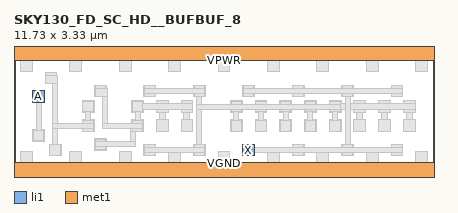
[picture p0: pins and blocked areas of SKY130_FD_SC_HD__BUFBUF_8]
MACRO SKY130_FD_SC_HD__BUFBUF_8
 CLASS CORE ;
 FOREIGN SKY130_FD_SC_HD__BUFBUF_8 0 0 ;
 SIZE 11.73 BY 3.33 ;
 ORIGIN 0 0 ;
 SYMMETRY X Y R90 ;
 SITE unit ;
  PIN VPWR
   DIRECTION INOUT ;
   USE POWER ;
   SHAPE ABUTMENT ;
    PORT
     CLASS CORE ;
       LAYER li1 ;
        RECT 0.00000000 3.09000000 11.73000000 3.57000000 ;
       LAYER met1 ;
        RECT 0.00000000 3.09000000 11.73000000 3.57000000 ;
    END
  END VPWR

  PIN VGND
   DIRECTION INOUT ;
   USE POWER ;
   SHAPE ABUTMENT ;
    PORT
     CLASS CORE ;
       LAYER li1 ;
        RECT 0.00000000 -0.24000000 11.73000000 0.24000000 ;
       LAYER met1 ;
        RECT 0.00000000 -0.24000000 11.73000000 0.24000000 ;
    END
  END VGND

  PIN X
   DIRECTION INOUT ;
   USE SIGNAL ;
   SHAPE ABUTMENT ;
    PORT
     CLASS CORE ;
       LAYER li1 ;
        RECT 6.39000000 0.42000000 6.72000000 0.75000000 ;
    END
  END X

  PIN A
   DIRECTION INOUT ;
   USE SIGNAL ;
   SHAPE ABUTMENT ;
    PORT
     CLASS CORE ;
       LAYER li1 ;
        RECT 0.52500000 1.90500000 0.85500000 2.23500000 ;
    END
  END A

 OBS
    LAYER polycont ;
     RECT 0.60500000 0.90500000 0.77500000 1.07500000 ;
     RECT 1.98500000 1.17500000 2.15500000 1.34500000 ;
     RECT 3.36500000 1.17500000 3.53500000 1.34500000 ;
     RECT 4.05500000 1.17500000 4.22500000 1.34500000 ;
     RECT 4.74500000 1.17500000 4.91500000 1.34500000 ;
     RECT 6.12500000 1.17500000 6.29500000 1.34500000 ;
     RECT 6.81500000 1.17500000 6.98500000 1.34500000 ;
     RECT 7.50500000 1.17500000 7.67500000 1.34500000 ;
     RECT 8.19500000 1.17500000 8.36500000 1.34500000 ;
     RECT 8.88500000 1.17500000 9.05500000 1.34500000 ;
     RECT 9.57500000 1.17500000 9.74500000 1.34500000 ;
     RECT 10.26500000 1.17500000 10.43500000 1.34500000 ;
     RECT 10.95500000 1.17500000 11.12500000 1.34500000 ;
     RECT 1.98500000 1.71500000 2.15500000 1.88500000 ;
     RECT 3.36500000 1.71500000 3.53500000 1.88500000 ;
     RECT 4.05500000 1.71500000 4.22500000 1.88500000 ;
     RECT 4.74500000 1.71500000 4.91500000 1.88500000 ;
     RECT 6.12500000 1.71500000 6.29500000 1.88500000 ;
     RECT 6.81500000 1.71500000 6.98500000 1.88500000 ;
     RECT 7.50500000 1.71500000 7.67500000 1.88500000 ;
     RECT 8.19500000 1.71500000 8.36500000 1.88500000 ;
     RECT 8.88500000 1.71500000 9.05500000 1.88500000 ;
     RECT 9.57500000 1.71500000 9.74500000 1.88500000 ;
     RECT 10.26500000 1.71500000 10.43500000 1.88500000 ;
     RECT 10.95500000 1.71500000 11.12500000 1.88500000 ;
     RECT 0.60500000 1.98500000 0.77500000 2.15500000 ;

    LAYER pdiffc ;
     RECT 2.33000000 2.15000000 2.50000000 2.32000000 ;
     RECT 3.71000000 2.15000000 3.88000000 2.32000000 ;
     RECT 5.09000000 2.15000000 5.26000000 2.32000000 ;
     RECT 6.47000000 2.15000000 6.64000000 2.32000000 ;
     RECT 7.85000000 2.15000000 8.02000000 2.32000000 ;
     RECT 9.23000000 2.15000000 9.40000000 2.32000000 ;
     RECT 10.61000000 2.15000000 10.78000000 2.32000000 ;
     RECT 0.95000000 2.51000000 1.12000000 2.68000000 ;
     RECT 0.26000000 2.86000000 0.43000000 3.03000000 ;
     RECT 1.64000000 2.86000000 1.81000000 3.03000000 ;
     RECT 3.02000000 2.86000000 3.19000000 3.03000000 ;
     RECT 4.40000000 2.86000000 4.57000000 3.03000000 ;
     RECT 5.78000000 2.86000000 5.95000000 3.03000000 ;
     RECT 7.16000000 2.86000000 7.33000000 3.03000000 ;
     RECT 8.54000000 2.86000000 8.71000000 3.03000000 ;
     RECT 9.92000000 2.86000000 10.09000000 3.03000000 ;
     RECT 11.30000000 2.86000000 11.47000000 3.03000000 ;

    LAYER ndiffc ;
     RECT 0.26000000 0.30000000 0.43000000 0.47000000 ;
     RECT 1.64000000 0.30000000 1.81000000 0.47000000 ;
     RECT 3.02000000 0.30000000 3.19000000 0.47000000 ;
     RECT 4.40000000 0.30000000 4.57000000 0.47000000 ;
     RECT 5.78000000 0.30000000 5.95000000 0.47000000 ;
     RECT 7.16000000 0.30000000 7.33000000 0.47000000 ;
     RECT 8.54000000 0.30000000 8.71000000 0.47000000 ;
     RECT 9.92000000 0.30000000 10.09000000 0.47000000 ;
     RECT 11.30000000 0.30000000 11.47000000 0.47000000 ;
     RECT 1.06500000 0.50000000 1.23500000 0.67000000 ;
     RECT 3.71000000 0.50000000 3.88000000 0.67000000 ;
     RECT 5.09000000 0.50000000 5.26000000 0.67000000 ;
     RECT 6.47000000 0.50000000 6.64000000 0.67000000 ;
     RECT 7.85000000 0.50000000 8.02000000 0.67000000 ;
     RECT 9.23000000 0.50000000 9.40000000 0.67000000 ;
     RECT 10.61000000 0.50000000 10.78000000 0.67000000 ;
     RECT 2.33000000 0.66000000 2.50000000 0.83000000 ;

    LAYER li1 ;
     RECT 0.00000000 -0.24000000 11.73000000 0.24000000 ;
     RECT 0.18000000 0.24000000 0.51000000 0.55000000 ;
     RECT 1.56000000 0.24000000 1.89000000 0.55000000 ;
     RECT 2.94000000 0.24000000 3.27000000 0.55000000 ;
     RECT 4.32000000 0.24000000 4.65000000 0.55000000 ;
     RECT 5.70000000 0.24000000 6.03000000 0.55000000 ;
     RECT 7.08000000 0.24000000 7.41000000 0.55000000 ;
     RECT 8.46000000 0.24000000 8.79000000 0.55000000 ;
     RECT 9.84000000 0.24000000 10.17000000 0.55000000 ;
     RECT 11.22000000 0.24000000 11.55000000 0.55000000 ;
     RECT 0.98500000 0.42000000 1.31500000 0.75000000 ;
     RECT 3.63000000 0.42000000 3.96000000 0.75000000 ;
     RECT 5.01000000 0.42000000 5.34000000 0.75000000 ;
     RECT 6.39000000 0.42000000 6.72000000 0.75000000 ;
     RECT 7.77000000 0.42000000 8.10000000 0.75000000 ;
     RECT 9.15000000 0.42000000 9.48000000 0.75000000 ;
     RECT 10.53000000 0.42000000 10.86000000 0.75000000 ;
     RECT 2.25000000 0.58000000 2.58000000 0.91000000 ;
     RECT 0.52500000 0.82500000 0.85500000 1.15500000 ;
     RECT 1.90500000 1.09500000 2.23500000 1.42500000 ;
     RECT 3.28500000 1.09500000 3.61500000 1.42500000 ;
     RECT 6.04500000 1.09500000 6.37500000 1.42500000 ;
     RECT 6.73500000 1.09500000 7.06500000 1.42500000 ;
     RECT 7.42500000 1.09500000 7.75500000 1.42500000 ;
     RECT 8.11500000 1.09500000 8.44500000 1.42500000 ;
     RECT 8.80500000 1.09500000 9.13500000 1.42500000 ;
     RECT 1.90500000 1.63500000 2.23500000 1.96500000 ;
     RECT 3.97500000 1.09500000 4.30500000 1.42500000 ;
     RECT 4.66500000 1.09500000 4.99500000 1.42500000 ;
     RECT 4.05500000 1.42500000 4.22500000 1.63500000 ;
     RECT 4.74500000 1.42500000 4.91500000 1.63500000 ;
     RECT 3.28500000 1.63500000 3.61500000 1.71500000 ;
     RECT 3.97500000 1.63500000 4.30500000 1.71500000 ;
     RECT 4.66500000 1.63500000 4.99500000 1.71500000 ;
     RECT 3.28500000 1.71500000 4.99500000 1.88500000 ;
     RECT 3.28500000 1.88500000 3.61500000 1.96500000 ;
     RECT 3.97500000 1.88500000 4.30500000 1.96500000 ;
     RECT 4.66500000 1.88500000 4.99500000 1.96500000 ;
     RECT 6.04500000 1.63500000 6.37500000 1.96500000 ;
     RECT 6.73500000 1.63500000 7.06500000 1.96500000 ;
     RECT 7.42500000 1.63500000 7.75500000 1.96500000 ;
     RECT 8.11500000 1.63500000 8.44500000 1.96500000 ;
     RECT 9.49500000 1.09500000 9.82500000 1.42500000 ;
     RECT 10.18500000 1.09500000 10.51500000 1.42500000 ;
     RECT 10.87500000 1.09500000 11.20500000 1.42500000 ;
     RECT 9.57500000 1.42500000 9.74500000 1.63500000 ;
     RECT 10.26500000 1.42500000 10.43500000 1.63500000 ;
     RECT 10.95500000 1.42500000 11.12500000 1.63500000 ;
     RECT 8.80500000 1.63500000 9.13500000 1.71500000 ;
     RECT 9.49500000 1.63500000 9.82500000 1.71500000 ;
     RECT 10.18500000 1.63500000 10.51500000 1.71500000 ;
     RECT 10.87500000 1.63500000 11.20500000 1.71500000 ;
     RECT 8.80500000 1.71500000 11.20500000 1.88500000 ;
     RECT 8.80500000 1.88500000 9.13500000 1.96500000 ;
     RECT 9.49500000 1.88500000 9.82500000 1.96500000 ;
     RECT 10.18500000 1.88500000 10.51500000 1.96500000 ;
     RECT 10.87500000 1.88500000 11.20500000 1.96500000 ;
     RECT 0.52500000 1.90500000 0.85500000 2.23500000 ;
     RECT 2.25000000 2.07000000 2.58000000 2.40000000 ;
     RECT 3.63000000 2.07000000 3.96000000 2.40000000 ;
     RECT 5.01000000 2.07000000 5.34000000 2.40000000 ;
     RECT 6.39000000 2.07000000 6.72000000 2.40000000 ;
     RECT 7.77000000 2.07000000 8.10000000 2.40000000 ;
     RECT 9.15000000 2.07000000 9.48000000 2.40000000 ;
     RECT 10.53000000 2.07000000 10.86000000 2.40000000 ;
     RECT 0.87000000 2.43000000 1.20000000 2.76000000 ;
     RECT 0.18000000 2.78000000 0.51000000 3.09000000 ;
     RECT 1.56000000 2.78000000 1.89000000 3.09000000 ;
     RECT 2.94000000 2.78000000 3.27000000 3.09000000 ;
     RECT 4.32000000 2.78000000 4.65000000 3.09000000 ;
     RECT 5.70000000 2.78000000 6.03000000 3.09000000 ;
     RECT 7.08000000 2.78000000 7.41000000 3.09000000 ;
     RECT 8.46000000 2.78000000 8.79000000 3.09000000 ;
     RECT 9.84000000 2.78000000 10.17000000 3.09000000 ;
     RECT 11.22000000 2.78000000 11.55000000 3.09000000 ;
     RECT 0.00000000 3.09000000 11.73000000 3.57000000 ;

    LAYER viali ;
     RECT 0.26000000 -0.08500000 0.43000000 0.08500000 ;
     RECT 1.06500000 0.50000000 1.23500000 0.67000000 ;
     RECT 3.71000000 0.50000000 3.88000000 0.67000000 ;
     RECT 5.09000000 0.50000000 5.26000000 0.67000000 ;
     RECT 6.47000000 0.50000000 6.64000000 0.67000000 ;
     RECT 7.85000000 0.50000000 8.02000000 0.67000000 ;
     RECT 9.23000000 0.50000000 9.40000000 0.67000000 ;
     RECT 10.61000000 0.50000000 10.78000000 0.67000000 ;
     RECT 2.33000000 0.66000000 2.50000000 0.83000000 ;
     RECT 0.60500000 0.90500000 0.77500000 1.07500000 ;
     RECT 1.98500000 1.17500000 2.15500000 1.34500000 ;
     RECT 3.36500000 1.17500000 3.53500000 1.34500000 ;
     RECT 6.12500000 1.17500000 6.29500000 1.34500000 ;
     RECT 6.81500000 1.17500000 6.98500000 1.34500000 ;
     RECT 7.50500000 1.17500000 7.67500000 1.34500000 ;
     RECT 8.19500000 1.17500000 8.36500000 1.34500000 ;
     RECT 8.88500000 1.17500000 9.05500000 1.34500000 ;
     RECT 1.98500000 1.71500000 2.15500000 1.88500000 ;
     RECT 3.36500000 1.71500000 3.53500000 1.88500000 ;
     RECT 6.12500000 1.71500000 6.29500000 1.88500000 ;
     RECT 6.81500000 1.71500000 6.98500000 1.88500000 ;
     RECT 7.50500000 1.71500000 7.67500000 1.88500000 ;
     RECT 8.19500000 1.71500000 8.36500000 1.88500000 ;
     RECT 8.88500000 1.71500000 9.05500000 1.88500000 ;
     RECT 0.60500000 1.98500000 0.77500000 2.15500000 ;
     RECT 2.33000000 2.15000000 2.50000000 2.32000000 ;
     RECT 3.71000000 2.15000000 3.88000000 2.32000000 ;
     RECT 5.09000000 2.15000000 5.26000000 2.32000000 ;
     RECT 6.47000000 2.15000000 6.64000000 2.32000000 ;
     RECT 7.85000000 2.15000000 8.02000000 2.32000000 ;
     RECT 9.23000000 2.15000000 9.40000000 2.32000000 ;
     RECT 10.61000000 2.15000000 10.78000000 2.32000000 ;
     RECT 0.95000000 2.51000000 1.12000000 2.68000000 ;
     RECT 4.40000000 3.24500000 4.57000000 3.41500000 ;

    LAYER met1 ;
     RECT 0.00000000 -0.24000000 11.73000000 0.24000000 ;
     RECT 0.54500000 0.84500000 0.83500000 1.13500000 ;
     RECT 0.62000000 1.13500000 0.76000000 1.92500000 ;
     RECT 0.54500000 1.92500000 0.83500000 2.21500000 ;
     RECT 2.27000000 0.60000000 2.56000000 0.67500000 ;
     RECT 2.27000000 0.67500000 3.40500000 0.81500000 ;
     RECT 2.27000000 0.81500000 2.56000000 0.89000000 ;
     RECT 3.26500000 0.81500000 3.40500000 1.11500000 ;
     RECT 3.26500000 1.11500000 3.59500000 1.19000000 ;
     RECT 2.46000000 1.19000000 3.59500000 1.33000000 ;
     RECT 3.30500000 1.33000000 3.59500000 1.40500000 ;
     RECT 3.38000000 1.40500000 3.52000000 1.65500000 ;
     RECT 3.30500000 1.65500000 3.59500000 1.94500000 ;
     RECT 2.46000000 1.33000000 2.60000000 2.09000000 ;
     RECT 2.27000000 2.09000000 2.60000000 2.30500000 ;
     RECT 2.27000000 2.30500000 2.56000000 2.38000000 ;
     RECT 3.65000000 0.44000000 3.94000000 0.51500000 ;
     RECT 5.03000000 0.44000000 5.32000000 0.51500000 ;
     RECT 3.65000000 0.51500000 5.32000000 0.65500000 ;
     RECT 3.65000000 0.65500000 3.94000000 0.73000000 ;
     RECT 5.03000000 0.65500000 5.32000000 0.73000000 ;
     RECT 6.06500000 1.11500000 6.35500000 1.40500000 ;
     RECT 6.75500000 1.11500000 7.04500000 1.40500000 ;
     RECT 7.44500000 1.11500000 7.73500000 1.40500000 ;
     RECT 8.13500000 1.11500000 8.42500000 1.40500000 ;
     RECT 8.82500000 1.11500000 9.11500000 1.40500000 ;
     RECT 6.14000000 1.40500000 6.28000000 1.65500000 ;
     RECT 6.83000000 1.40500000 6.97000000 1.65500000 ;
     RECT 7.52000000 1.40500000 7.66000000 1.65500000 ;
     RECT 8.21000000 1.40500000 8.35000000 1.65500000 ;
     RECT 8.90000000 1.40500000 9.04000000 1.65500000 ;
     RECT 5.10500000 0.73000000 5.24500000 1.73000000 ;
     RECT 6.06500000 1.65500000 6.35500000 1.73000000 ;
     RECT 6.75500000 1.65500000 7.04500000 1.73000000 ;
     RECT 7.44500000 1.65500000 7.73500000 1.73000000 ;
     RECT 8.13500000 1.65500000 8.42500000 1.73000000 ;
     RECT 8.82500000 1.65500000 9.11500000 1.73000000 ;
     RECT 5.10500000 1.73000000 9.11500000 1.87000000 ;
     RECT 6.06500000 1.87000000 6.35500000 1.94500000 ;
     RECT 6.75500000 1.87000000 7.04500000 1.94500000 ;
     RECT 7.44500000 1.87000000 7.73500000 1.94500000 ;
     RECT 8.13500000 1.87000000 8.42500000 1.94500000 ;
     RECT 8.82500000 1.87000000 9.11500000 1.94500000 ;
     RECT 5.10500000 1.87000000 5.24500000 2.09000000 ;
     RECT 3.65000000 2.09000000 3.94000000 2.16500000 ;
     RECT 5.03000000 2.09000000 5.32000000 2.16500000 ;
     RECT 3.65000000 2.16500000 5.32000000 2.30500000 ;
     RECT 3.65000000 2.30500000 3.94000000 2.38000000 ;
     RECT 5.03000000 2.30500000 5.32000000 2.38000000 ;
     RECT 6.41000000 0.44000000 6.70000000 0.51500000 ;
     RECT 7.79000000 0.44000000 8.08000000 0.51500000 ;
     RECT 9.17000000 0.44000000 9.46000000 0.51500000 ;
     RECT 10.55000000 0.44000000 10.84000000 0.51500000 ;
     RECT 6.41000000 0.51500000 10.84000000 0.65500000 ;
     RECT 6.41000000 0.65500000 6.70000000 0.73000000 ;
     RECT 7.79000000 0.65500000 8.08000000 0.73000000 ;
     RECT 9.17000000 0.65500000 9.46000000 0.73000000 ;
     RECT 10.55000000 0.65500000 10.84000000 0.73000000 ;
     RECT 9.24500000 0.73000000 9.38500000 2.09000000 ;
     RECT 6.41000000 2.09000000 6.70000000 2.16500000 ;
     RECT 7.79000000 2.09000000 8.08000000 2.16500000 ;
     RECT 9.17000000 2.09000000 9.46000000 2.16500000 ;
     RECT 10.55000000 2.09000000 10.84000000 2.16500000 ;
     RECT 6.41000000 2.16500000 10.84000000 2.30500000 ;
     RECT 6.41000000 2.30500000 6.70000000 2.38000000 ;
     RECT 7.79000000 2.30500000 8.08000000 2.38000000 ;
     RECT 9.17000000 2.30500000 9.46000000 2.38000000 ;
     RECT 10.55000000 2.30500000 10.84000000 2.38000000 ;
     RECT 1.00500000 0.44000000 1.29500000 0.73000000 ;
     RECT 1.08000000 0.73000000 1.22000000 1.19000000 ;
     RECT 1.92500000 1.11500000 2.21500000 1.19000000 ;
     RECT 1.08000000 1.19000000 2.21500000 1.33000000 ;
     RECT 1.92500000 1.33000000 2.21500000 1.40500000 ;
     RECT 2.00000000 1.40500000 2.14000000 1.65500000 ;
     RECT 1.92500000 1.65500000 2.21500000 1.94500000 ;
     RECT 1.08000000 1.33000000 1.22000000 2.45000000 ;
     RECT 0.89000000 2.45000000 1.22000000 2.66500000 ;
     RECT 0.89000000 2.66500000 1.18000000 2.74000000 ;
     RECT 0.00000000 3.09000000 11.73000000 3.57000000 ;

    LAYER via ;


    LAYER met2 ;


    LAYER via2 ;


    LAYER met3 ;


 END
END SKY130_FD_SC_HD__BUFBUF_8
